VERSION 5.8 ;
UNITS
 DATABASE MICRONS 1000 ;
END UNITS
LAYER M1
 TYPE ROUTING ;
 DIRECTION HORIZONTAL ;
 PITCH 0.1 ;
 WIDTH 0.04 ;
 SPACING 0.04 ;
END M1
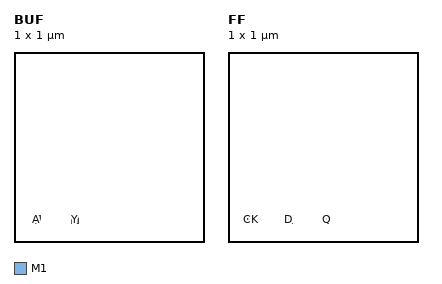
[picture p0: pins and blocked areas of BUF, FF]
MACRO BUF
 CLASS CORE ;
 ORIGIN 0 0 ;
 SIZE 1 BY 1 ;
 PIN A
  DIRECTION INPUT ;
  USE SIGNAL ;
  PORT
   LAYER M1 ;
   RECT 0.1 0.1 0.14 0.14 ;
  END
 END A
 PIN Y
  DIRECTION OUTPUT ;
  USE SIGNAL ;
  PORT
   LAYER M1 ;
   RECT 0.3 0.1 0.34 0.14 ;
  END
 END Y
END BUF
MACRO FF
 CLASS BLOCK ;
 ORIGIN 0 0 ;
 SIZE 1 BY 1 ;
 PIN CK
  DIRECTION INPUT ;
  USE CLOCK ;
  PORT
   LAYER M1 ;
   RECT 0.1 0.1 0.14 0.14 ;
  END
 END CK
 PIN D
  DIRECTION INPUT ;
  USE SIGNAL ;
  PORT
   LAYER M1 ;
   RECT 0.3 0.1 0.34 0.14 ;
  END
 END D
 PIN Q
  DIRECTION OUTPUT ;
  USE SIGNAL ;
  PORT
   LAYER M1 ;
   RECT 0.5 0.1 0.54 0.14 ;
  END
 END Q
END FF
END LIBRARY
